VERSION 5.7 ;
  NOWIREEXTENSIONATPIN ON ;
  DIVIDERCHAR "/" ;
  BUSBITCHARS "[]" ;
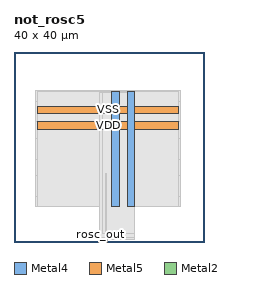
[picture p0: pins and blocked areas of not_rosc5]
MACRO not_rosc5
  CLASS BLOCK ;
  FOREIGN not_rosc5 ;
  ORIGIN 0.000 0.000 ;
  SIZE 40.000 BY 40.000 ;
  PIN VDD
    DIRECTION INOUT ;
    USE POWER ;
    PORT
      LAYER Metal4 ;
        RECT 20.560 7.540 22.160 31.660 ;
    END
    PORT
      LAYER Metal5 ;
        RECT 5.040 23.690 34.720 25.290 ;
    END
  END VDD
  PIN VSS
    DIRECTION INOUT ;
    USE GROUND ;
    PORT
      LAYER Metal4 ;
        RECT 23.860 7.540 25.460 31.660 ;
    END
    PORT
      LAYER Metal5 ;
        RECT 5.040 26.990 34.720 28.590 ;
    END
  END VSS
  PIN rosc_enable
    DIRECTION INPUT ;
    USE SIGNAL ;
    ANTENNAGATEAREA 1.057000 ;
    PORT
      LAYER Metal2 ;
        RECT 19.040 0.000 19.600 0.560 ;
    END
  END rosc_enable
  PIN rosc_out
    DIRECTION OUTPUT ;
    USE SIGNAL ;
    ANTENNADIFFAREA 1.986000 ;
    PORT
      LAYER Metal2 ;
        RECT 17.920 0.000 18.480 0.560 ;
    END
  END rosc_out
  OBS
      LAYER Pwell ;
        RECT 4.610 29.600 35.150 31.790 ;
      LAYER Nwell ;
        RECT 4.610 25.280 35.150 29.600 ;
      LAYER Pwell ;
        RECT 4.610 21.760 35.150 25.280 ;
      LAYER Nwell ;
        RECT 4.610 17.440 35.150 21.760 ;
      LAYER Pwell ;
        RECT 4.610 13.920 35.150 17.440 ;
      LAYER Nwell ;
        RECT 4.610 9.600 35.150 13.920 ;
      LAYER Pwell ;
        RECT 4.610 7.410 35.150 9.600 ;
      LAYER Metal1 ;
        RECT 5.040 7.540 34.720 31.660 ;
      LAYER Metal2 ;
        RECT 18.060 0.860 25.320 31.550 ;
        RECT 19.900 0.560 25.320 0.860 ;
      LAYER Metal3 ;
        RECT 18.570 1.820 25.370 31.500 ;
      LAYER Metal4 ;
        RECT 19.180 1.770 19.460 14.470 ;
  END
END not_rosc5
END LIBRARY

